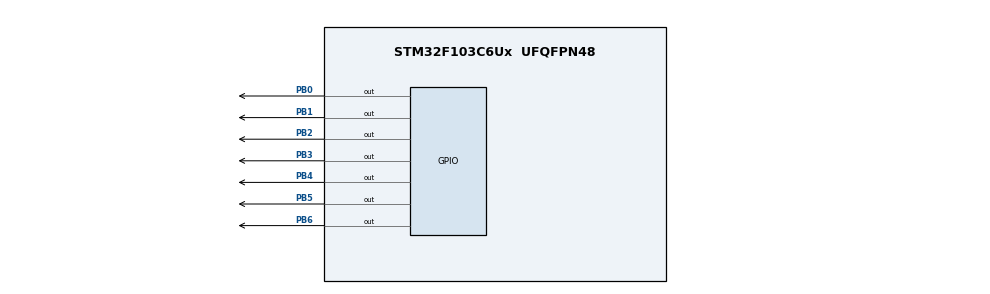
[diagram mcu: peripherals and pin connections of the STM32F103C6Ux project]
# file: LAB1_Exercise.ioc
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Mcu.Family=STM32F1
Mcu.Name=STM32F103C6Ux
Mcu.Package=UFQFPN48
NVIC.PriorityGroup=NVIC_PRIORITYGROUP_4
PB0.Signal=GPIO_Output
PB1.Signal=GPIO_Output
PB2.Signal=GPIO_Output
PB3.Signal=GPIO_Output
PB4.Signal=GPIO_Output
PB5.Signal=GPIO_Output
PB6.Signal=GPIO_Output
ProjectManager.HeapSize=0x200
ProjectManager.StackSize=0x400
ProjectManager.TargetToolchain=STM32CubeIDE
RCC.APB1Freq_Value=8000000
RCC.APB2Freq_Value=8000000
VP_SYS_VS_ND.Mode=No_Debug
board=custom

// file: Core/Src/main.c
/* USER CODE BEGIN Header */
/**
  ******************************************************************************
  * @file           : main.c
  * @brief          : Main program body
  ******************************************************************************
  * @attention
  *
  * <h2><center>&copy; Copyright (c) 2021 STMicroelectronics.
  * All rights reserved.</center></h2>
  *
  * This software component is licensed by ST under BSD 3-Clause license,
  * the "License"; You may not use this file except in compliance with the
  * License. You may obtain a copy of the License at:
  *                        opensource.org/licenses/BSD-3-Clause
  *
  ******************************************************************************
  */
/* USER CODE END Header */
#include "main.h"

void SystemClock_Config(void);
static void MX_GPIO_Init(void);
void clearAllClock();
void setNumberOnClock(int num);
void clearNumberOnClock(int num);

int main(void)
{

  /* MCU Configuration--------------------------------------------------------*/

  /* Reset of all peripherals, Initializes the Flash interface and the Systick. */
  HAL_Init();

  /* Configure the system clock */
  SystemClock_Config();

  /* Initialize all configured peripherals */
  MX_GPIO_Init();

  /* Infinite loop */
  /* USER CODE BEGIN WHILE */
  int n_sec = 0;
  int n_min = 0;
  int n_hour = 0;
  clearAllClock();
  while (1)
  {
	if (n_sec == 60) {
		n_sec = 0;
		n_min++;
	}
	else if (n_min == 60) {
		n_min = 0;
		n_hour++;
	}
	else if (n_hour == 12) {
		n_hour = 0;
	}
	clearAllClock();
	setNumberOnClock(n_hour);
	setNumberOnClock(n_min/5);
	setNumberOnClock(n_sec/5);
	n_sec++;
	HAL_Delay(10);
    /* USER CODE END WHILE */

  }
}

void SystemClock_Config(void)
{
  RCC_OscInitTypeDef RCC_OscInitStruct = {0};
  RCC_ClkInitTypeDef RCC_ClkInitStruct = {0};

  /** Initializes the RCC Oscillators according to the specified parameters
  * in the RCC_OscInitTypeDef structure.
  */
  RCC_OscInitStruct.OscillatorType = RCC_OSCILLATORTYPE_HSI;
  RCC_OscInitStruct.HSIState = RCC_HSI_ON;
  RCC_OscInitStruct.HSICalibrationValue = RCC_HSICALIBRATION_DEFAULT;
  RCC_OscInitStruct.PLL.PLLState = RCC_PLL_NONE;
  if (HAL_RCC_OscConfig(&RCC_OscInitStruct) != HAL_OK)
  {
    Error_Handler();
  }
  /** Initializes the CPU, AHB and APB buses clocks
  */
  RCC_ClkInitStruct.ClockType = RCC_CLOCKTYPE_HCLK|RCC_CLOCKTYPE_SYSCLK
                              |RCC_CLOCKTYPE_PCLK1|RCC_CLOCKTYPE_PCLK2;
  RCC_ClkInitStruct.SYSCLKSource = RCC_SYSCLKSOURCE_HSI;
  RCC_ClkInitStruct.AHBCLKDivider = RCC_SYSCLK_DIV1;
  RCC_ClkInitStruct.APB1CLKDivider = RCC_HCLK_DIV1;
  RCC_ClkInitStruct.APB2CLKDivider = RCC_HCLK_DIV1;

  if (HAL_RCC_ClockConfig(&RCC_ClkInitStruct, FLASH_LATENCY_0) != HAL_OK)
  {
    Error_Handler();
  }
}

static void MX_GPIO_Init(void)
{
  GPIO_InitTypeDef GPIO_InitStruct = {0};

  /* GPIO Ports Clock Enable */
  __HAL_RCC_GPIOA_CLK_ENABLE();

  /*Configure GPIO pin Output Level */
  HAL_GPIO_WritePin(GPIOA, GPIO_PIN_4|GPIO_Output_Pin|GPIO_OutputA6_Pin|GPIO_OutputA7_Pin
                          |GPIO_PIN_8|GPIO_PIN_9|GPIO_PIN_10|GPIO_PIN_11
                          |GPIO_PIN_12|GPIO_PIN_13|GPIO_PIN_14|GPIO_PIN_15, GPIO_PIN_RESET);

  /*Configure GPIO pins : PA4 GPIO_Output_Pin GPIO_OutputA6_Pin GPIO_OutputA7_Pin
                           PA8 PA9 PA10 PA11
                           PA12 PA13 PA14 PA15 */
  GPIO_InitStruct.Pin = GPIO_PIN_4|GPIO_Output_Pin|GPIO_OutputA6_Pin|GPIO_OutputA7_Pin
                          |GPIO_PIN_8|GPIO_PIN_9|GPIO_PIN_10|GPIO_PIN_11
                          |GPIO_PIN_12|GPIO_PIN_13|GPIO_PIN_14|GPIO_PIN_15;
  GPIO_InitStruct.Mode = GPIO_MODE_OUTPUT_PP;
  GPIO_InitStruct.Pull = GPIO_NOPULL;
  GPIO_InitStruct.Speed = GPIO_SPEED_FREQ_LOW;
  HAL_GPIO_Init(GPIOA, &GPIO_InitStruct);

}

/* USER CODE BEGIN 4 */
void clearAllClock()
{
	/**
	 * Turn off all LEDs
	 */
	HAL_GPIO_WritePin(GPIOA, 0xffff, GPIO_PIN_SET); //1
}

void setNumberOnClock(int num)
{
	/**
	 * Turn on the corresponding LED, num must be from 0 to 11
	 *
	 */
    static const uint16_t ledPins[] = {
        GPIO_PIN_4, GPIO_PIN_5, GPIO_PIN_6, GPIO_PIN_7,
        GPIO_PIN_8, GPIO_PIN_9, GPIO_PIN_10, GPIO_PIN_11,
        GPIO_PIN_12, GPIO_PIN_13, GPIO_PIN_14, GPIO_PIN_15
    };
    HAL_GPIO_WritePin(GPIOA, ledPins[num], GPIO_PIN_RESET);//0
//	HAL_GPIO_WritePin(GPIOA, GPIO_PIN_4 << num, GPIO_PIN_RESET);//0
}
void clearNumberOnClock(int num)
{
	/**
	 * Turn off the corresponding LED, num must be from 0 to 11
	 */
    static const uint16_t ledPins[] = {
        GPIO_PIN_4, GPIO_PIN_5, GPIO_PIN_6, GPIO_PIN_7,
        GPIO_PIN_8, GPIO_PIN_9, GPIO_PIN_10, GPIO_PIN_11,
        GPIO_PIN_12, GPIO_PIN_13, GPIO_PIN_14, GPIO_PIN_15
    };
    HAL_GPIO_WritePin(GPIOA, ledPins[num], GPIO_PIN_SET);//0
//	HAL_GPIO_WritePin(GPIOA, GPIO_PIN_4 << num, GPIO_PIN_SET);//1
}
/* USER CODE END 4 */

void Error_Handler(void)
{
  __disable_irq();
  while (1)
  {
  }
}

/************************ (C) COPYRIGHT STMicroelectronics *****END OF FILE****/
